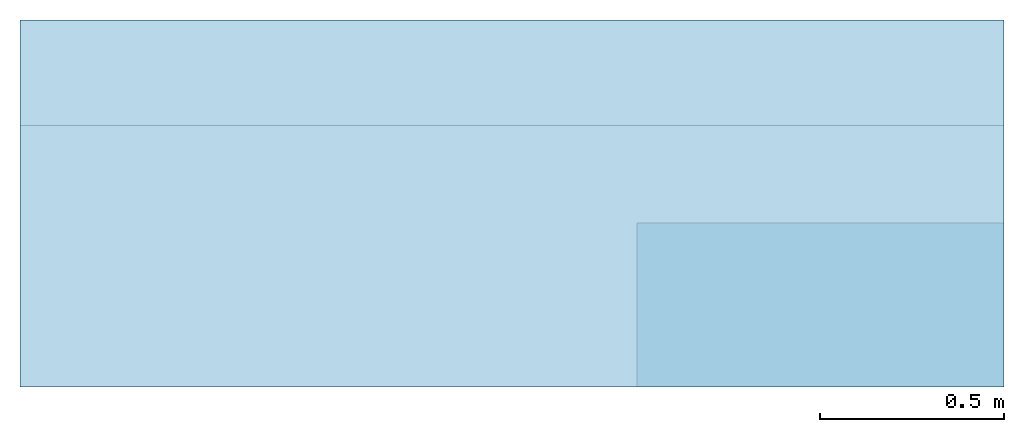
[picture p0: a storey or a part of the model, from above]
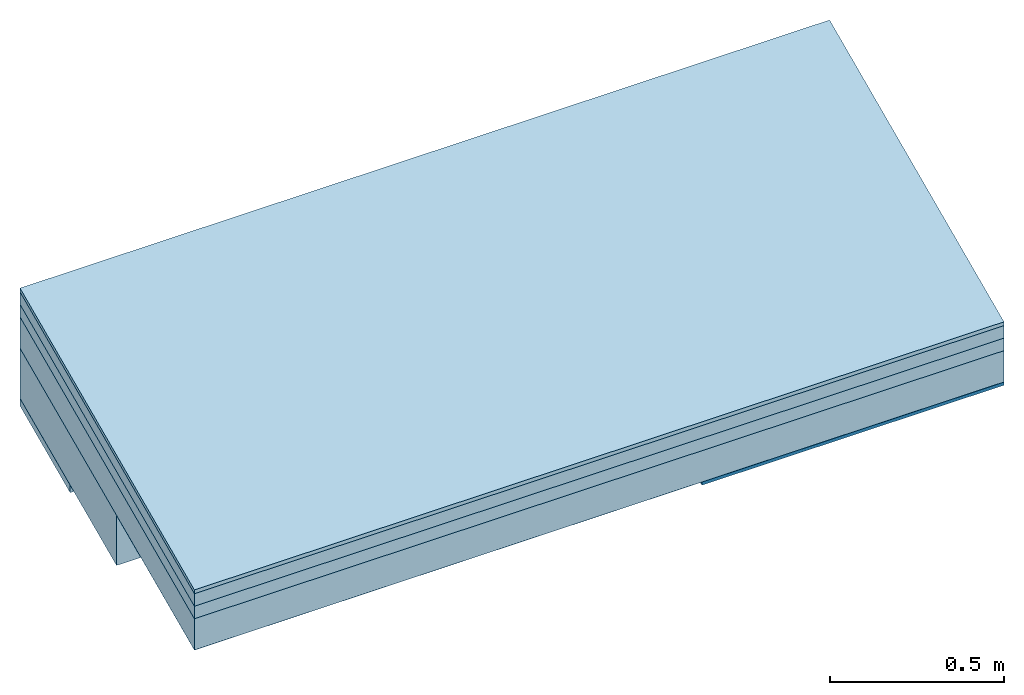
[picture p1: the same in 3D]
Properties of the parts of a building model (IFC4)

# File
Description: ViewDefinition [ReferenceView_V1.2], RevitIdentifiers [ContentGUID: d45b1106-0c7a-46e1-869b-c6a7bbcc7ea5, VersionGUID: 118b0530-1591-4ac2-8939-a10ffb714872, NumberOfSaves: 70], CoordinateReference [CoordinateBase: Internal Origin, ProjectSite: Internal], ExchangeRequirement [Architecture]
File name: 3dv__Detail__15__208, WS25, Door, F90, Vertical_WIP Copy 1 Copy 1 Copy 1.ifc
Time: 2025-12-19T14:28:55+01:00
Written by: ODA SDAI 25.12
Made in: Autodesk - Revit 26.3.0.37 (ENU) - 26.4.1.0

# IfcSite, Default
RefLatitude: 45, 45, 37, 23925; RefLongitude: 21, 14, 26, 780090; RefElevation: 0 cm

# IfcBuildingStorey (10)
Name | LongName | Elevation (cm)
B2__ABOVE Slab | B2__ABOVE Slab | -612
B1__ABOVE Slab | B1__ABOVE Slab | -312
L00__ABOVE Slab | L00__ABOVE Slab | -12
L01__ABOVE Slab | L01__ABOVE Slab | 273
L02__ABOVE Slab | L02__ABOVE Slab | 558
L03__ABOVE Slab | L03__ABOVE Slab | 843
L04__ABOVE Slab | L04__ABOVE Slab | 1128
L05__ABOVE Slab | L05__ABOVE Slab | 1413
L06__ABOVE Slab | L06__ABOVE Slab | 1698
L07__ABOVE Slab | L07__ABOVE Slab | 1983

# IfcBuildingElementPart (6)
Name | In | Material
_FCD FINISH__Wood | L00__ABOVE Slab | _FCD FINISH__Wood
Default Wall | L02__ABOVE Slab | Default Wall
_FCD LAYERS__Insulation__Wood-fiber__Steico | L02__ABOVE Slab | _FCD LAYERS__Insulation__Wood-fiber__Steico
_FCD FINISH__Spray-cork | L02__ABOVE Slab | _FCD FINISH__Spray-cork
_FCD LAYERS__Insulation__EPS 120__Austrotherm EPS A120 | L02__ABOVE Slab | _FCD LAYERS__Insulation__EPS 120__Austrotherm EPS A120
_WLL & CLG FINISHES__Lime - CEM Plaster | L02__ABOVE Slab | _WLL & CLG FINISHES__Lime - CEM Plaster

# IfcCovering: Roof Soffits : Roof Soffit : Roof Soffit 1
In: L00__ABOVE Slab
Type - PredefinedType: CLADDING

# IfcPipeSegment: Gutters : Gutter : Gutter
In: L03__ABOVE Slab
Type - PredefinedType: GUTTER

# IfcRoof (6)
In: L00__ABOVE Slab
Name (Parts :...) | Material
 Part | _SL ROOF FINISH__Clay Tiles__Tondach
 Part | _SL ROOF LAYERS__Horizontal Counter Battens__WD, 60x40mm
 Part | _SL ROOF LAYERS__Ventilated Air Space / Vertical Battens__WD, 60x40mm
2 x  Part | _SL ROOF LAYERS__Insulation__MW abv Rafters__Rockwool Hardrock 700
 Part | _SL ROOF LAYERS__Decking Board__WD

# IfcWall: Columns : wll_s__DECOUPLING BEAM__Rectangular__wp : Wood
In: L02__ABOVE Slab
Type - PredefinedType: SOLIDWALL; Material: _STRUCTURE__Wood Solid
Classification: A 1.0.3 (Uniformat)

# IfcWall: Columns : wll_s__TIMBER BLOCK__Triqbriq, Full Width__wp1 : WS25 2 (19)
In: L02__ABOVE Slab
Type - PredefinedType: SOLIDWALL; Material: Miscellaneous__Timber Block__Triqbriq, Y
Classification: A 1.0.1 (Uniformat)

# IfcWall: Walls : Basic Wall : wll__EXT ENCLOSURE__Spritzkork, Wood Insulation 10.6cm__TriqBriq, FS.3 3
In: L02__ABOVE Slab
Type - PredefinedType: STANDARD
Classification: A 4.3.4.2.1 Pereti exteriori (Uniformat)

# IfcWall: Walls : Basic Wall : wll__INT FINISH__Spritzkork, Lime - CEM Plaster 2.4cm TRIQBRIQ
In: L02__ABOVE Slab
Type - PredefinedType: STANDARD
Classification: A 7.1.1 Tencuieli umede (Uniformat)
